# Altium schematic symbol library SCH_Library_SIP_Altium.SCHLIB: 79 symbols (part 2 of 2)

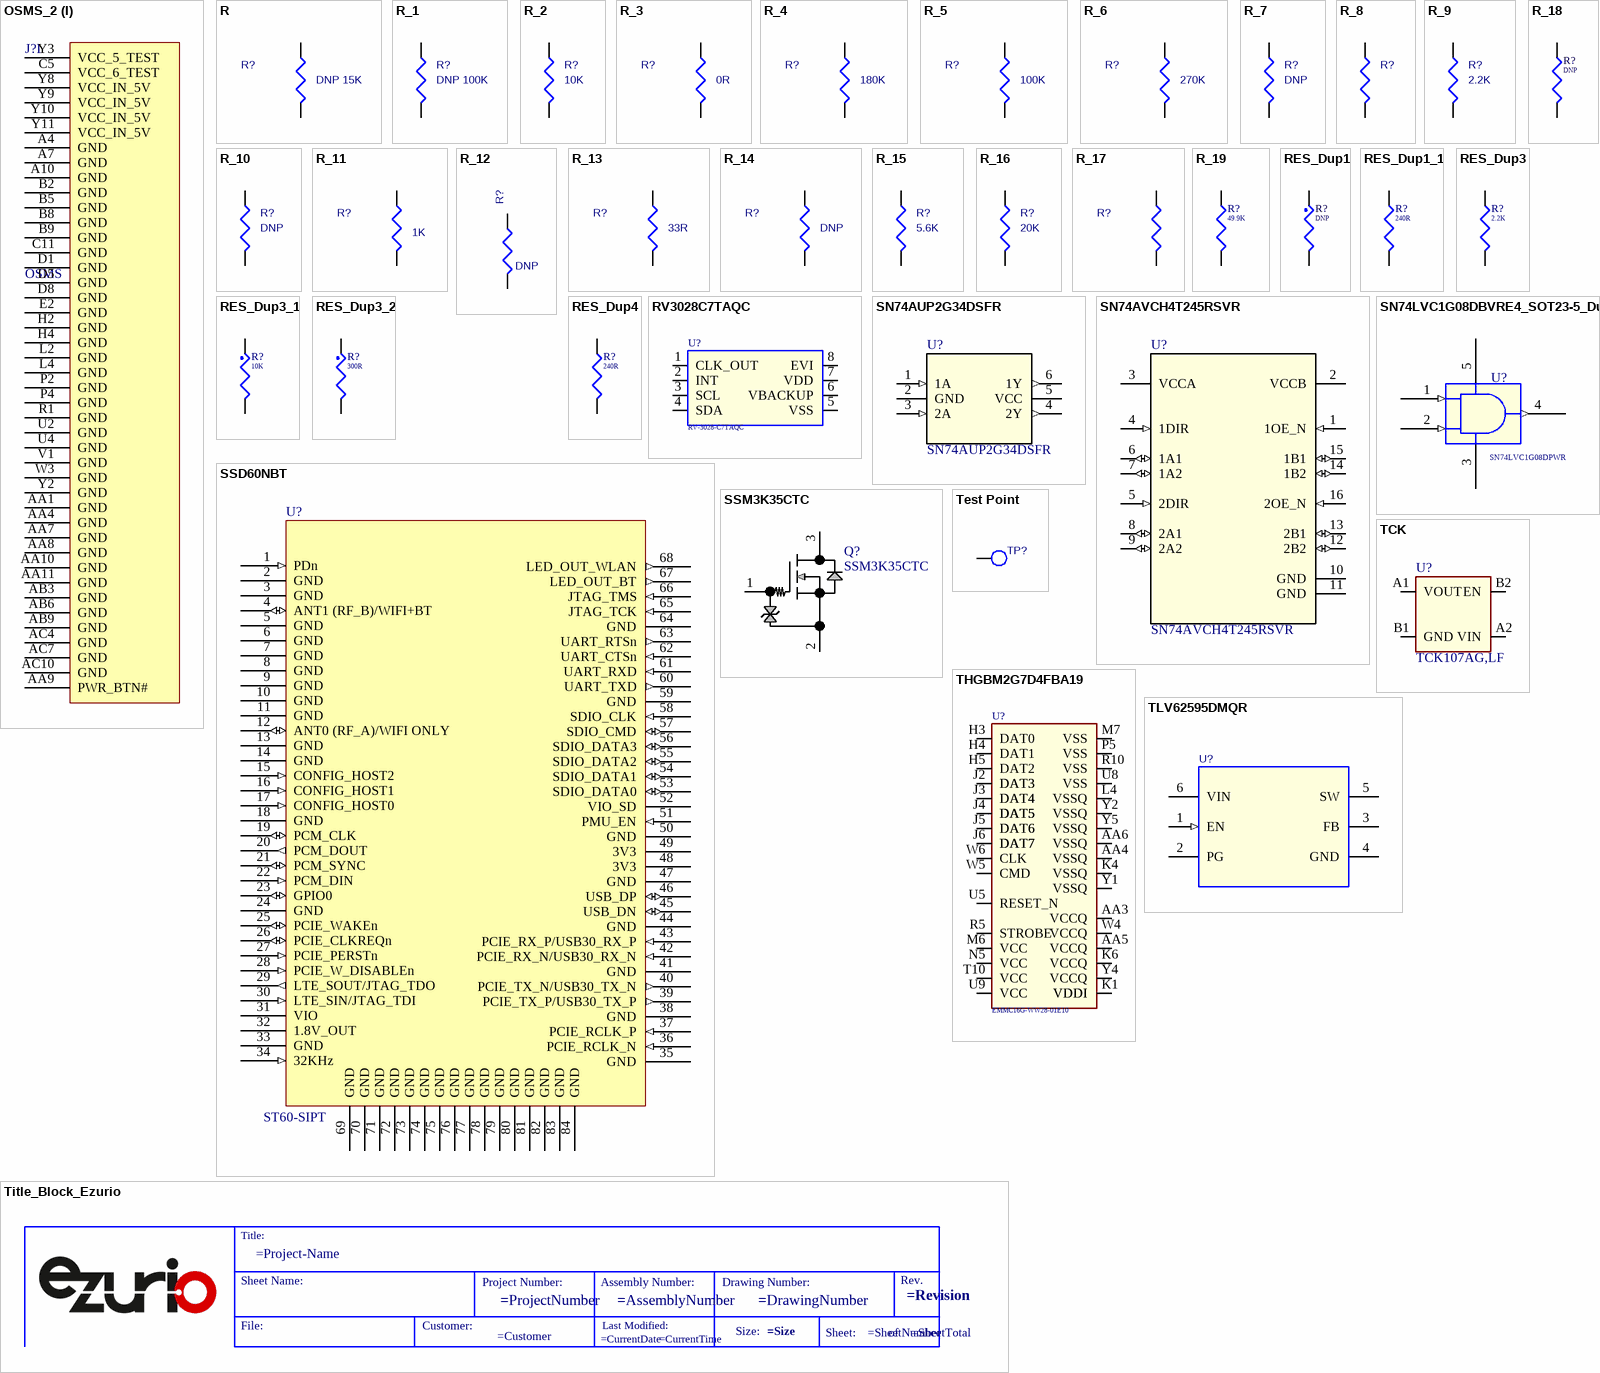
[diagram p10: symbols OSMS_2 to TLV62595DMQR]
## SN74AVCH4T245RSVR
designator U?
IC TRANSLATION TXRX 3.6V 16UQFN; 01. ASET1 UI1: ------------; 01. Set1/BD#: BD3717; 02. Set1/MF1: Texas Instruments
footprint RSV0016A
footprint SN74AVCH4T245RSVR
pins: 1 1OE_N (in), 2 VCCB (power), 3 VCCA (power), 4 1DIR (in), 5 2DIR (in), 6 1A1 (io), 7 1A2 (io), 8 2A1 (io), 9 2A2 (io), 10 GND (power), 11 GND (power), 12 2B2 (io), 13 2B1 (io), 14 1B2 (io), 15 1B1 (io), 16 2OE_N (in)

## SN74LVC1G08DBVRE4_SOT23-5_Dup1
designator U?, comment SN74LVC1G08DPWR
IC GATE AND 1CH 2-INP 4X2SON; 01. ASET1 UI1: ------------; 01. Set1/BD#: BD3789; 02. Set1/MF1: Texas Instruments
footprint SOT23-5
footprint SN74LVC1G08DPWR
pins: 1 A (in), 2 B (in), 3 GND (power), 4 Y (out), 5 VCC (power)

## SSD60NBT
designator U?, comment ST60-SIPT
Module Sterling 60 SIP-; 01. ASET1 UI1: ------------; 02. Set1/MF1: Ezurio
footprint ST60-SIPT
pins: 1 PDn (in), 2 GND (power), 3 GND (power), 4 ANT1 (RF_B)/WIFI+BT (io), 5 GND (power), 6 GND (power), 7 GND (power), 8 GND (power), 9 GND (power), 10 GND (power), 11 GND (power), 12 ANT0 (RF_A)/WIFI ONLY (io), 13 GND (power), 14 GND (power), 15 CONFIG_HOST2 (in), 16 CONFIG_HOST1 (in), 17 CONFIG_HOST0 (in), 18 GND (power), 19 PCM_CLK (io), 20 PCM_DOUT (out), 21 PCM_SYNC (io), 22 PCM_DIN (in), 23 GPIO0 (io), 24 GND (power), 25 PCIE_WAKEn (io), 26 PCIE_CLKREQn (io), 27 PCIE_PERSTn (in), 28 PCIE_W_DISABLEn (in), 29 LTE_SOUT/JTAG_TDO (out), 30 LTE_SIN/JTAG_TDI (in), 31 VIO (power), 32 1.8V_OUT (power), 33 GND (power), 34 32KHz (in), 35 GND (power), 36 PCIE_RCLK_N (in), 37 PCIE_RCLK_P (in), 38 GND (power), 39 PCIE_TX_P/USB30_TX_P (out), 40 PCIE_TX_N/USB30_TX_N (out), 41 GND (power), 42 PCIE_RX_N/USB30_RX_N (in), 43 PCIE_RX_P/USB30_RX_P (in), 44 GND (power), 45 USB_DN (io), 46 USB_DP (io), 47 GND (power), 48 3V3 (power), 49 3V3 (power), 50 GND (power), 51 PMU_EN (in), 52 VIO_SD (power), 53 SDIO_DATA0 (io), 54 SDIO_DATA1 (io), 55 SDIO_DATA2 (io), 56 SDIO_DATA3 (io), 57 SDIO_CMD (io), 58 SDIO_CLK (in), 59 GND (power), 60 UART_TXD (out), 61 UART_RXD (in), 62 UART_CTSn (in), 63 UART_RTSn (out), 64 GND (power), 65 JTAG_TCK (in), 66 JTAG_TMS (in), 67 LED_OUT_BT (out), 68 LED_OUT_WLAN (out), 69 GND (power), 70 GND (power), 71 GND (power), 72 GND (power), 73 GND (power), 74 GND (power), 75 GND (power), 76 GND (power), 77 GND (power), 78 GND (power), 79 GND (power), 80 GND (power), 81 GND (power), 82 GND (power), 83 GND (power), 84 GND (power)

## SSM3K35CTC
designator Q?
MOSFET N-CH 20V 250MA CST3C; 01. ASET1 UI1: ------------; 01. Set1/BD#: BD3417; 09. Z Lay/FP: SSM3K35CTC,L3F; 02. Set1/MF1: Toshiba Semiconductor
footprint SSM3K35CTC,L3F
pins: 1, 2, 3

## TCK
designator U?, comment TCK107AG,LF
IC PWR SWITCH P-CHAN 1:1 4WCSPD; 01. ASET1 UI1: ------------; 01. Set1/BD#: BD3329; 02. Set1/MF1: Toshiba
footprint TCK107AG,LF
pins: A1 VOUT, A2 VIN, B1 GND, B2 EN

## Test Point
designator TP?  (value not drawn)  (no BOM)
MISC, Test Point, Test Point, SMD, TP35S_SMD; 01. ASET1 UI1: ------------; 09. Z Lay/FP: TPAD_020_OSM
footprint tp1-8040
footprint TP35S_SMD
footprint tpad_020
footprint TPAD_020_OSM
pins: 1 TP

## THGBM2G7D4FBA19
designator U?, comment EMMC16G-WW28-01E10
16G EMMC Industrial; 01. ASET1 UI1: ------------; 01. Set1/BD#: BD3431; 02. Set1/MF1: Kingston; 09. Footprint/Package: BGA-153; 09. Z Lay/FP: THGBM2G7D4FBA19_2
footprint THGBM2G7D4FBA19_2
pins: AA3 VCCQ, AA4 VSSQ, AA5 VCCQ, AA6 VSSQ, H1 DAT3, H2 DAT4, H3 DAT0, H4 DAT1, H5 DAT2, H8 DAT7, J2 DAT3, J3 DAT4, J4 DAT5, J5 DAT6, J6 DAT7, J7 DAT7, K1 VDDI, K2 VDDI, K3 DAT5, K4 VSSQ, K5 DAT6, K6 VCCQ, L1 DAT5, L2 DAT5, L4 VSSQ, M6 VCC, M7 VSS, N5 VCC, P5 VSS, R5 STROBE, R10 VSS, T10 VCC, U5 RESET_N, U8 VSS, U9 VCC, W4 VCCQ, W5 CMD, W6 CLK, Y1 VSSQ, Y2 VSSQ, Y4 VCCQ, Y5 VSSQ

## Title_Block_Ezurio
designator ??  (value not drawn)  (graphical)

## TLV62595DMQR
designator U?  (value not drawn)
IC REG BUCK ADJ 4A 6VSON; 01. ASET1 UI1: ------------; 01. Set1/BD#: BD3327; 02. Set1/MF1: Texas Instruments
footprint vson6_0d5_1d5x1d5x1mm
footprint TLV62595DMQR
pins: 1 EN (in), 2 PG (oc), 3 FB, 4 GND (power), 5 SW, 6 VIN (power)


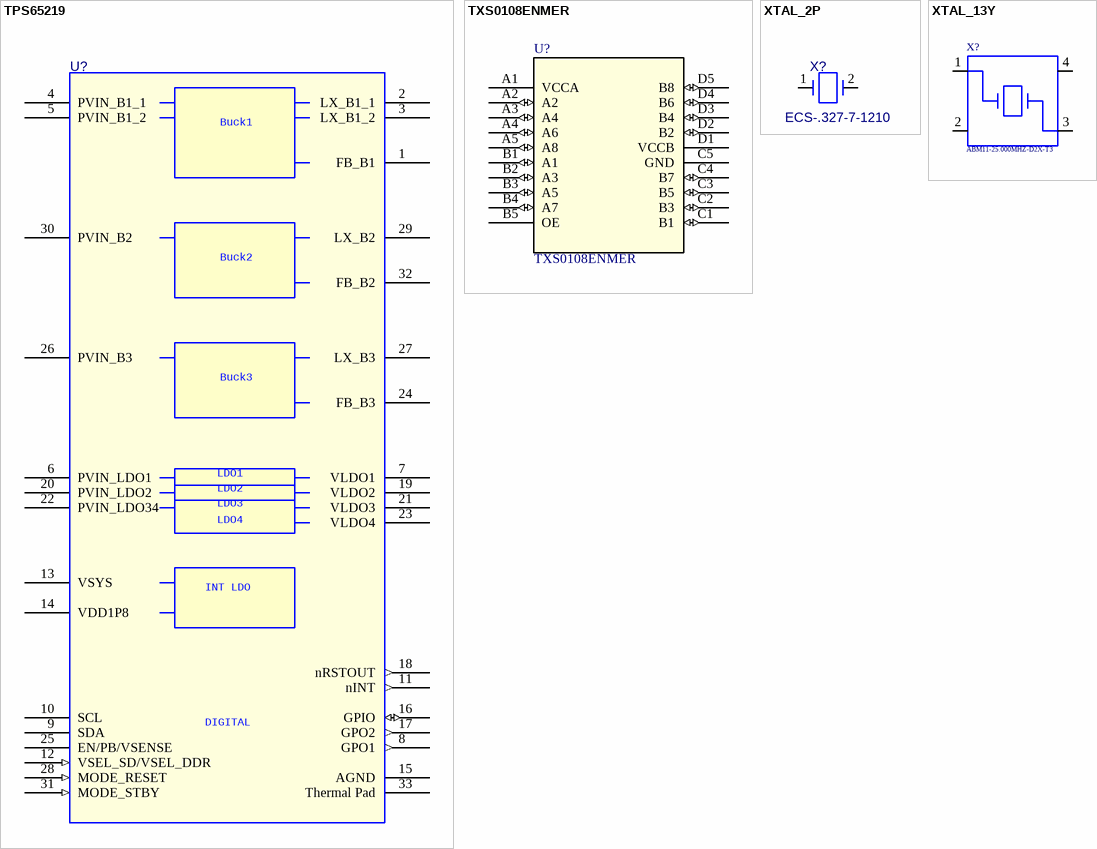
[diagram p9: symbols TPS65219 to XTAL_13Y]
## TPS65219
designator U?, comment TPS6521920WRHBRQ1  (value not drawn)
Processor PMIC 32-VQFN (5x5); 01. ASET1 UI1: ------------; 01. Set1/BD#: BD3428; 02. Set1/MF1: Texas Instruments
footprint QFN32_5X5MM_TPS65219
footprint TPS6521920W
pins: 1 FB_B1, 2 LX_B1_1, 3 LX_B1_2, 4 PVIN_B1_1 (power), 5 PVIN_B1_2 (power), 6 PVIN_LDO1 (power), 7 VLDO1 (power), 8 GPO1 (out), 9 SDA, 10 SCL, 11 nINT (out), 12 VSEL_SD/VSEL_DDR (in), 13 VSYS (power), 14 VDD1P8, 15 AGND (power), 16 GPIO (io), 17 GPO2 (out), 18 nRSTOUT (out), 19 VLDO2 (power), 20 PVIN_LDO2 (power), 21 VLDO3 (power), 22 PVIN_LDO34 (power), 23 VLDO4 (power), 24 FB_B3, 25 EN/PB/VSENSE, 26 PVIN_B3 (power), 27 LX_B3, 28 MODE_RESET (in), 29 LX_B2, 30 PVIN_B2 (power), 31 MODE_STBY (in), 32 FB_B2, 33 Thermal Pad (power)

## TXS0108ENMER
designator U?
IC TRANSLATOR BIDIR 20NFBGA; 01. ASET1 UI1: ------------; 01. Set1/BD#: BD3427; 02. Set1/MF1: Texas Instruments
footprint TXS0108ENMER
pins: A1 VCCA (power), A2 (io), A3 A4 (io), A4 A6 (io), A5 A8 (io), B1 A1 (io), B2 A3 (io), B3 A5 (io), B4 A7 (io), B5 OE, C1 B1 (io), C2 B3 (io), C3 B5 (io), C4 B7 (io), C5 GND (power), D1 VCCB (power), D2 B2 (io), D3 B4 (io), D4 B6 (io), D5 B8 (io)

## XTAL_2P
designator X?, comment ECS-.327-7-1210
CRYSTAL 32.7680KHZ 7PF SMD; 01. ASET1 UI1: ------------; 01. Set1/BD#: BD3426; 02. Set1/MF1: ECS Inc.; 03. Set1/PN1: ECS-.327-7-1210-TR; 09. Z Lay/FP: XTAL_ECS-.327-7-1210-TR
footprint X2_SMD_3_2X1_5MM
footprint XTAL_ABS07
footprint XTAL_ECS-.327-7-1210-TR
pins: 1, 2

## XTAL_13Y
designator X?, comment ABM11-25.000MHZ-D2X-T3
CRYSTAL 25.0000MHZ 10PF SMD; 01. ASET1 UI1: ------------; 01. Set1/BD#: BD3424; 02. Set1/MF1: Abracon LLC; 09. Z Lay/FP: ECS-250-10-47Q-CES-TR
footprint XTAL_ABM11
footprint ECS-250-10-47Q-CES-TR
pins: 1, 2, 3, 4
